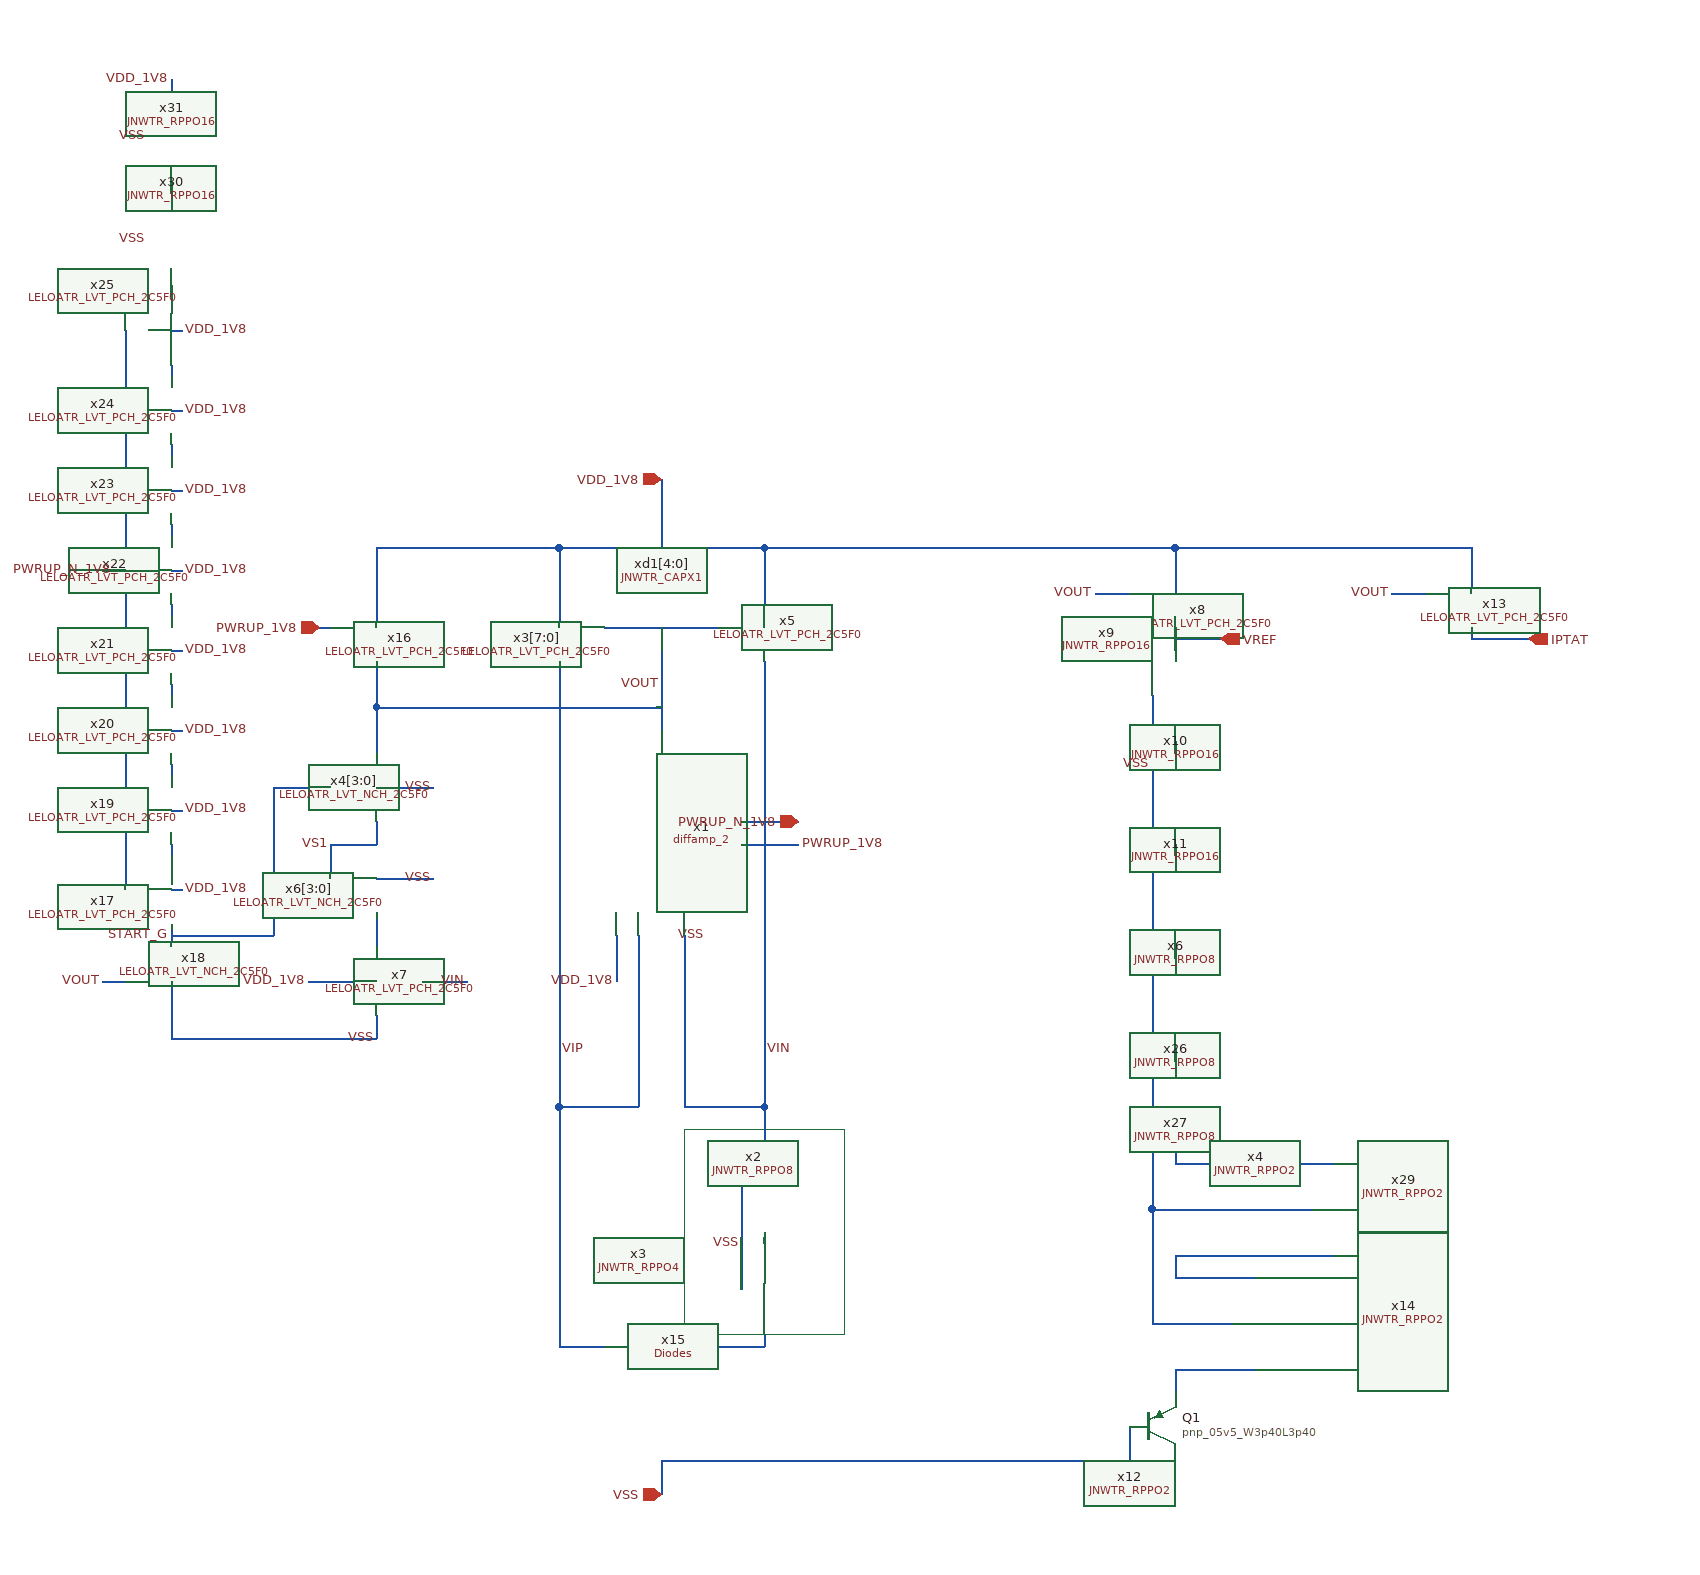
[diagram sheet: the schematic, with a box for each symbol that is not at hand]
v {xschem version=3.4.7 file_version=1.2}
G {}
K {}
V {}
S {}
E {}
L 4 20 440 160 440 {}
L 4 160 440 160 620 {}
L 4 20 620 160 620 {}
L 4 20 440 20 620 {}
P 4 1 60 -60 {}
P 4 1 -130 -150 {}
P 4 1 -80 420 {}
P 4 1 -290 700 {}
P 4 1 -430 420 {}
N 0 0 0 90 {lab=VOUT}
N -90 30 -90 420 {lab=VIP}
N -90 -30 -90 0 {lab=VDD_1V8}
N 0 -120 0 -100 {lab=VDD_1V8}
N -90 -50 -90 -30 {lab=VDD_1V8}
N -40 270 -40 310 {lab=VDD_1V8}
N -90 420 -20 420 {lab=VIP}
N 0 730 0 760 {lab=VSS}
N -50 0 50 0 {lab=VOUT}
N 90 -50 90 -30 {lab=VDD_1V8}
N -90 -70 90 -70 {lab=VDD_1V8}
N 90 -70 90 -50 {lab=VDD_1V8}
N -90 -70 -90 -50 {lab=VDD_1V8}
N -0 -100 -0 -70 {lab=VDD_1V8}
N 0 730 50 730 {lab=#net1}
N 90 420 90 450 {lab=VIN}
N 20 420 90 420 {lab=VIN}
N 70 490 70 580 {lab=VSS}
N 90 530 90 540 {lab=#net2}
N 90 -30 90 -0 {lab=VDD_1V8}
N -250 70 -250 110 {lab=VOUT}
N -250 70 0 70 {lab=VOUT}
N -250 140 -200 140 {lab=VSS}
N -250 220 -200 220 {lab=VSS}
N -250 170 -250 190 {lab=VS1}
N -290 190 -250 190 {lab=VS1}
N -290 190 -290 220 {lab=VS1}
N -210 310 -170 310 {lab=VIN}
N -310 310 -250 310 {lab=VDD_1V8}
N -250 250 -250 280 {lab=#net3}
N -250 340 -250 360 {lab=VSS}
N -20 270 -20 330 {lab=VIP}
N 20 270 20 330 {lab=VIN}
N 90 -70 250 -70 {lab=VDD_1V8}
N 380 -30 410 -30 {lab=VOUT}
N 450 10 490 10 {lab=VREF}
N 450 100 450 110 {lab=#net4}
N 450 190 450 200 {lab=#net5}
N 50 730 250 730 {lab=#net1}
N 410 700 410 730 {lab=#net1}
N 430 60 430 240 {lab=VSS}
N 450 280 450 290 {lab=#net6}
N 430 240 430 330 {lab=VSS}
N -20 330 -20 420 {lab=VIP}
N 20 330 20 420 {lab=VIN}
N 90 30 90 70 {lab=VIN}
N 90 70 90 100 {lab=VIN}
N 90 130 90 370 {lab=VIN}
N 90 370 90 420 {lab=VIN}
N 250 -70 440 -70 {lab=VDD_1V8}
N 250 730 450 730 {lab=#net1}
N 440 -70 450 -70 {lab=VDD_1V8}
N 90 100 90 130 {lab=VIN}
N 450 -70 710 -70 {lab=VDD_1V8}
N 640 -30 670 -30 {lab=VOUT}
N 710 10 760 10 {lab=IPTAT}
N 70 190 120 190 {lab=PWRUP_1V8}
N 70 170 120 170 {lab=PWRUP_N_1V8}
N -250 -70 -90 -70 {lab=VDD_1V8}
N -490 310 -470 310 {lab=VOUT}
N -430 310 -430 340 {lab=VSS}
N -430 340 -430 360 {lab=VSS}
N -430 360 -250 360 {lab=VSS}
N -430 260 -430 280 {lab=START_G}
N -470 -260 -470 230 {lab=PWRUP_N_1V8}
N -490 -50 -470 -50 {lab=PWRUP_N_1V8}
N -430 -300 -430 -290 {lab=#net7}
N -430 270 -340 270 {lab=START_G}
N -340 140 -340 270 {lab=START_G}
N -340 140 -290 140 {lab=START_G}
N 430 330 430 510 {lab=VSS}
N 450 460 450 470 {lab=#net8}
N 450 370 450 380 {lab=#net9}
N 430 510 500 510 {lab=VSS}
N 450 550 520 550 {lab=#net10}
N 450 470 520 470 {lab=#net8}
N -430 -90 -430 -80 {lab=#net11}
N -430 -160 -430 -150 {lab=#net12}
N -430 -230 -430 -220 {lab=#net13}
N -430 -20 -430 -10 {lab=#net14}
N -430 50 -430 60 {lab=#net15}
N -430 120 -430 130 {lab=#net16}
N -430 190 -430 200 {lab=#net17}
N -430 230 -420 230 {lab=VDD_1V8}
N -430 160 -420 160 {lab=VDD_1V8}
N -430 90 -420 90 {lab=VDD_1V8}
N -430 20 -420 20 {lab=VDD_1V8}
N -430 -50 -420 -50 {lab=VDD_1V8}
N -430 -120 -420 -120 {lab=VDD_1V8}
N -430 -190 -420 -190 {lab=VDD_1V8}
N -430 -260 -420 -260 {lab=VDD_1V8}
N 710 -70 710 -30 {lab=VDD_1V8}
N 450 -70 450 -30 {lab=VDD_1V8}
N 450 -0 450 20 {lab=VREF}
N 710 -0 710 10 {lab=IPTAT}
N -90 420 -90 460 {lab=VIP}
N 450 650 450 670 {lab=#net18}
N 450 550 450 570 {lab=#net10}
N 430 510 430 610 {lab=VSS}
N -300 0 -290 0 {lab=PWRUP_1V8}
N -250 -70 -250 -30 {lab=VDD_1V8}
N -250 30 -250 70 {lab=VOUT}
N -250 -30 -250 0 {lab=VDD_1V8}
N -0 -130 0 -120 {lab=VDD_1V8}
N 450 570 520 570 {lab=#net10}
N 450 650 520 650 {lab=#net18}
N 430 610 500 610 {lab=VSS}
N -430 -390 -430 -380 {lab=#net19}
N -430 -480 -430 -470 {lab=VDD_1V8}
N 520 550 590 550 {lab=#net10}
N 500 510 570 510 {lab=VSS}
N 520 470 590 470 {lab=#net8}
N 40 630 90 630 {lab=#net20}
N 90 620 90 630 {lab=#net20}
N -90 460 -90 630 {lab=VIP}
N -90 630 -50 630 {lab=VIP}
C {devices/lab_wire.sym} -40 310 0 0 {name=p2 sig_type=std_logic lab=VDD_1V8}
C {devices/lab_wire.sym} 40 270 3 0 {name=p6 sig_type=std_logic lab=VSS}
C {devices/ipin.sym} 0 -130 0 0 {name=p7 lab=VDD_1V8}
C {devices/ipin.sym} 0 760 0 0 {name=p11 lab=VSS}
C {LELO_ATR_SKY130A/LELOATR_LVT_PCH_2C5F0.sym} 50 0 0 0 {name=x5}
C {LELO_ATR_SKY130A/LELOATR_LVT_PCH_2C5F0.sym} -50 0 0 1 {name=x3[7:0]}
C {JNW_TR_SKY130A/JNWTR_CAPX1.sym} 0 -60 2 1 {name=xd1[4:0]}
C {devices/lab_wire.sym} 90 370 2 0 {name=p3 sig_type=std_logic lab=VIN}
C {devices/lab_wire.sym} -90 370 2 0 {name=p5 sig_type=std_logic lab=VIP
}
C {JNW_TR_SKY130A/JNWTR_RPPO8.sym} 90 450 1 0 {name=x2 }
C {JNW_TR_SKY130A/JNWTR_RPPO4.sym} 90 540 1 0 {name=x3 }
C {devices/lab_wire.sym} 70 540 0 0 {name=p14 sig_type=std_logic lab=VSS}
C {LELO_ATR_SKY130A/LELOATR_LVT_NCH_2C5F0.sym} -290 140 0 0 {name=x4[3:0]}
C {LELO_ATR_SKY130A/LELOATR_LVT_NCH_2C5F0.sym} -290 220 0 0 {name=x6[3:0]}
C {devices/lab_wire.sym} -200 140 0 0 {name=p17 sig_type=std_logic lab=VSS}
C {devices/lab_wire.sym} -200 220 0 0 {name=p18 sig_type=std_logic lab=VSS}
C {LELO_ATR_SKY130A/LELOATR_LVT_PCH_2C5F0.sym} -210 310 0 1 {name=x7}
C {devices/lab_wire.sym} -170 310 0 0 {name=p19 sig_type=std_logic lab=VIN
}
C {devices/lab_wire.sym} -310 310 0 0 {name=p20 sig_type=std_logic lab=VDD_1V8}
C {devices/lab_wire.sym} -250 360 0 0 {name=p21 sig_type=std_logic lab=VSS}
C {devices/opin.sym} 760 10 0 0 {name=p23 lab=IPTAT}
C {LELO_ATR_SKY130A/LELOATR_LVT_PCH_2C5F0.sym} 410 -30 0 0 {name=x8}
C {devices/lab_wire.sym} 380 -30 0 0 {name=p16 sig_type=std_logic lab=VOUT}
C {devices/opin.sym} 490 10 0 0 {name=p24 lab=VREF}
C {JNW_TR_SKY130A/JNWTR_RPPO16.sym} 450 20 1 0 {name=x9}
C {JNW_TR_SKY130A/JNWTR_RPPO16.sym} 450 110 1 0 {name=x10 }
C {JNW_TR_SKY130A/JNWTR_RPPO16.sym} 450 200 1 0 {name=x11 }
C {sky130_fd_pr/pnp_05v5.sym} 430 700 0 0 {name=Q1
model=pnp_05v5_W3p40L3p40
m=1
spiceprefix=X
}
C {devices/lab_wire.sym} 430 120 0 0 {name=p25 sig_type=std_logic lab=VSS}
C {LELO_GR01_SKY130A/diffamp_2.sym} 0 120 3 0 {name=x1}
C {devices/lab_wire.sym} 0 50 0 0 {name=p9 sig_type=std_logic lab=VOUT}
C {devices/lab_wire.sym} -290 190 0 0 {name=p26 sig_type=std_logic lab=VS1}
C {JNW_TR_SKY130A/JNWTR_RPPO8.sym} 450 290 1 0 {name=x6}
C {LELO_ATR_SKY130A/LELOATR_LVT_PCH_2C5F0.sym} 670 -30 0 0 {name=x13}
C {devices/lab_wire.sym} 640 -30 0 0 {name=p8 sig_type=std_logic lab=VOUT}
C {devices/ipin.sym} -300 0 0 0 {name=p1 lab=PWRUP_1V8}
C {devices/ipin.sym} 120 170 2 0 {name=p13 lab=PWRUP_N_1V8}
C {devices/lab_wire.sym} 120 190 2 0 {name=p15 sig_type=std_logic lab=PWRUP_1V8}
C {LELO_ATR_SKY130A/LELOATR_LVT_PCH_2C5F0.sym} -290 0 0 0 {name=x16}
C {LELO_ATR_SKY130A/LELOATR_LVT_PCH_2C5F0.sym} -470 230 0 0 {name=x17}
C {LELO_ATR_SKY130A/LELOATR_LVT_NCH_2C5F0.sym} -470 310 0 0 {name=x18 }
C {devices/lab_wire.sym} -490 310 0 0 {name=p22 sig_type=std_logic lab=VOUT}
C {LELO_ATR_SKY130A/LELOATR_LVT_PCH_2C5F0.sym} -470 160 0 0 {name=x19}
C {LELO_ATR_SKY130A/LELOATR_LVT_PCH_2C5F0.sym} -470 90 0 0 {name=x20}
C {LELO_ATR_SKY130A/LELOATR_LVT_PCH_2C5F0.sym} -470 20 0 0 {name=x21}
C {LELO_ATR_SKY130A/LELOATR_LVT_PCH_2C5F0.sym} -470 -50 0 0 {name=x22}
C {LELO_ATR_SKY130A/LELOATR_LVT_PCH_2C5F0.sym} -470 -120 0 0 {name=x23}
C {LELO_ATR_SKY130A/LELOATR_LVT_PCH_2C5F0.sym} -470 -190 0 0 {name=x24}
C {LELO_ATR_SKY130A/LELOATR_LVT_PCH_2C5F0.sym} -470 -260 0 0 {name=x25}
C {devices/lab_wire.sym} -430 270 0 0 {name=p27 sig_type=std_logic lab=START_G
}
C {devices/lab_wire.sym} -480 -50 2 1 {name=p28 sig_type=std_logic lab=PWRUP_N_1V8}
C {devices/lab_wire.sym} -430 -480 0 0 {name=p29 sig_type=std_logic lab=VDD_1V8}
C {JNW_TR_SKY130A/JNWTR_RPPO8.sym} 450 380 1 0 {name=x26}
C {JNW_TR_SKY130A/JNWTR_RPPO8.sym} 450 470 1 0 {name=x27}
C {JNW_TR_SKY130A/JNWTR_RPPO2.sym} 520 470 1 0 {name=x4}
C {devices/lab_wire.sym} -420 230 0 1 {name=p4 sig_type=std_logic lab=VDD_1V8}
C {devices/lab_wire.sym} -420 160 0 1 {name=p10 sig_type=std_logic lab=VDD_1V8}
C {devices/lab_wire.sym} -420 90 0 1 {name=p12 sig_type=std_logic lab=VDD_1V8}
C {devices/lab_wire.sym} -420 20 0 1 {name=p30 sig_type=std_logic lab=VDD_1V8}
C {devices/lab_wire.sym} -420 -50 0 1 {name=p31 sig_type=std_logic lab=VDD_1V8}
C {devices/lab_wire.sym} -420 -120 0 1 {name=p32 sig_type=std_logic lab=VDD_1V8}
C {devices/lab_wire.sym} -420 -190 0 1 {name=p33 sig_type=std_logic lab=VDD_1V8}
C {devices/lab_wire.sym} -420 -260 0 1 {name=p34 sig_type=std_logic lab=VDD_1V8}
C {JNW_TR_SKY130A/JNWTR_RPPO2.sym} 450 570 1 0 {name=x12}
C {JNW_TR_SKY130A/JNWTR_RPPO2.sym} 520 570 1 0 {name=x14}
C {JNW_TR_SKY130A/JNWTR_RPPO16.sym} -430 -380 1 0 {name=x30 }
C {devices/lab_wire.sym} -450 -340 0 0 {name=p35 sig_type=std_logic lab=VSS}
C {JNW_TR_SKY130A/JNWTR_RPPO16.sym} -430 -470 1 0 {name=x31 }
C {devices/lab_wire.sym} -450 -430 0 0 {name=p36 sig_type=std_logic lab=VSS}
C {JNW_TR_SKY130A/JNWTR_RPPO2.sym} 590 470 1 0 {name=x29}
C {LELO_GR01_SKY130A/Diodes.sym} -60 680 0 0 {name=x15}
